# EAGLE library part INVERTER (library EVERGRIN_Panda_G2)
Inverter

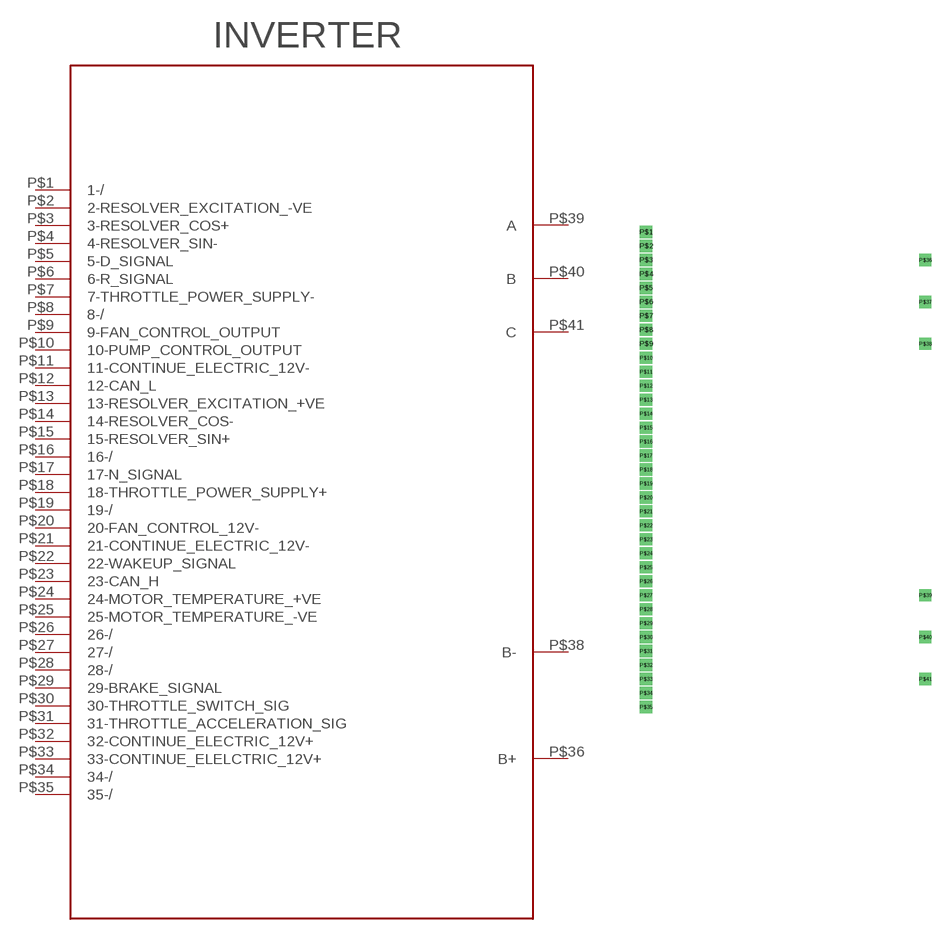
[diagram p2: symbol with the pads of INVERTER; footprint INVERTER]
Designator prefix -

## INVERTER  [INVERTER]
P$1  1-/
P$2  2-RESOLVER_EXCITATION_-VE
P$3  3-RESOLVER_COS+
P$4  4-RESOLVER_SIN-
P$5  5-D_SIGNAL
P$6  6-R_SIGNAL
P$7  7-THROTTLE_POWER_SUPPLY-
P$8  8-/
P$9  9-FAN_CONTROL_OUTPUT
P$10  10-PUMP_CONTROL_OUTPUT
P$11  11-CONTINUE_ELECTRIC_12V-
P$12  12-CAN_L
P$13  13-RESOLVER_EXCITATION_+VE
P$14  14-RESOLVER_COS-
P$15  15-RESOLVER_SIN+
P$16  16-/
P$17  17-N_SIGNAL
P$18  18-THROTTLE_POWER_SUPPLY+
P$19  19-/
P$20  20-FAN_CONTROL_12V-
P$21  21-CONTINUE_ELECTRIC_12V-
P$22  22-WAKEUP_SIGNAL
P$23  23-CAN_H
P$24  24-MOTOR_TEMPERATURE_+VE
P$25  25-MOTOR_TEMPERATURE_-VE
P$26  26-/
P$27  27-/
P$28  28-/
P$29  29-BRAKE_SIGNAL
P$30  30-THROTTLE_SWITCH_SIG
P$31  31-THROTTLE_ACCELERATION_SIG
P$32  32-CONTINUE_ELECTRIC_12V+
P$33  33-CONTINUE_ELELCTRIC_12V+
P$34  34-/
P$35  35-/
P$36  B+
P$38  B-
P$39  A
P$40  B
P$41  C

## Footprint INVERTER (pad centres in mm)
drill 0.6 square: P$1 -6.35,54.61; P$2 -6.35,53.34; P$3 -6.35,52.07; P$4 -6.35,50.8; P$5 -6.35,49.53; P$6 -6.35,48.26; P$7 -6.35,46.99; P$8 -6.35,45.72; P$9 -6.35,44.45; P$10 -6.35,43.18; P$11 -6.35,41.91; P$12 -6.35,40.64; P$13 -6.35,39.37; P$14 -6.35,38.1; P$15 -6.35,36.83; P$16 -6.35,35.56; P$17 -6.35,34.29; P$18 -6.35,33.02; P$19 -6.35,31.75; P$20 -6.35,30.48; P$21 -6.35,29.21; P$22 -6.35,27.94; P$23 -6.35,26.67; P$24 -6.35,25.4; P$25 -6.35,24.13; P$26 -6.35,22.86; P$27 -6.35,21.59; P$28 -6.35,20.32; P$29 -6.35,19.05; P$30 -6.35,17.78; P$31 -6.35,16.51; P$32 -6.35,15.24; P$33 -6.35,13.97; P$34 -6.35,12.7; P$35 -6.35,11.43; P$36 19.05,52.07; P$37 19.05,48.26; P$38 19.05,44.45; P$39 19.05,21.59; P$40 19.05,17.78; P$41 19.05,13.97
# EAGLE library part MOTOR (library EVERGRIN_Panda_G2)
Motor

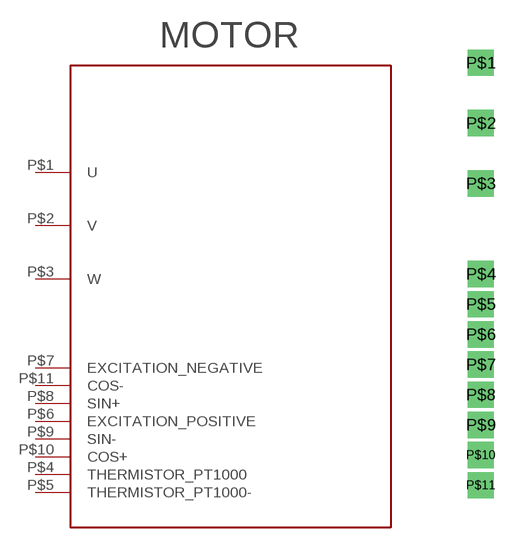
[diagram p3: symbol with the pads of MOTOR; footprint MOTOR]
Designator prefix -

## MOTOR  [MOTOR]
P$1  U
P$2  V
P$3  W
P$4  THERMISTOR_PT1000
P$5  THERMISTOR_PT1000-
P$6  EXCITATION_POSITIVE
P$7  EXCITATION_NEGATIVE
P$8  SIN+
P$9  SIN-
P$10  COS+
P$11  COS-

## Footprint MOTOR (pad centres in mm)
drill 0.6 square: P$1 -1.27,24.13; P$2 -1.27,21.59; P$3 -1.27,19.05; P$4 -1.27,15.24; P$5 -1.27,13.97; P$6 -1.27,12.7; P$7 -1.27,11.43; P$8 -1.27,10.16; P$9 -1.27,8.89; P$10 -1.27,7.62; P$11 -1.27,6.35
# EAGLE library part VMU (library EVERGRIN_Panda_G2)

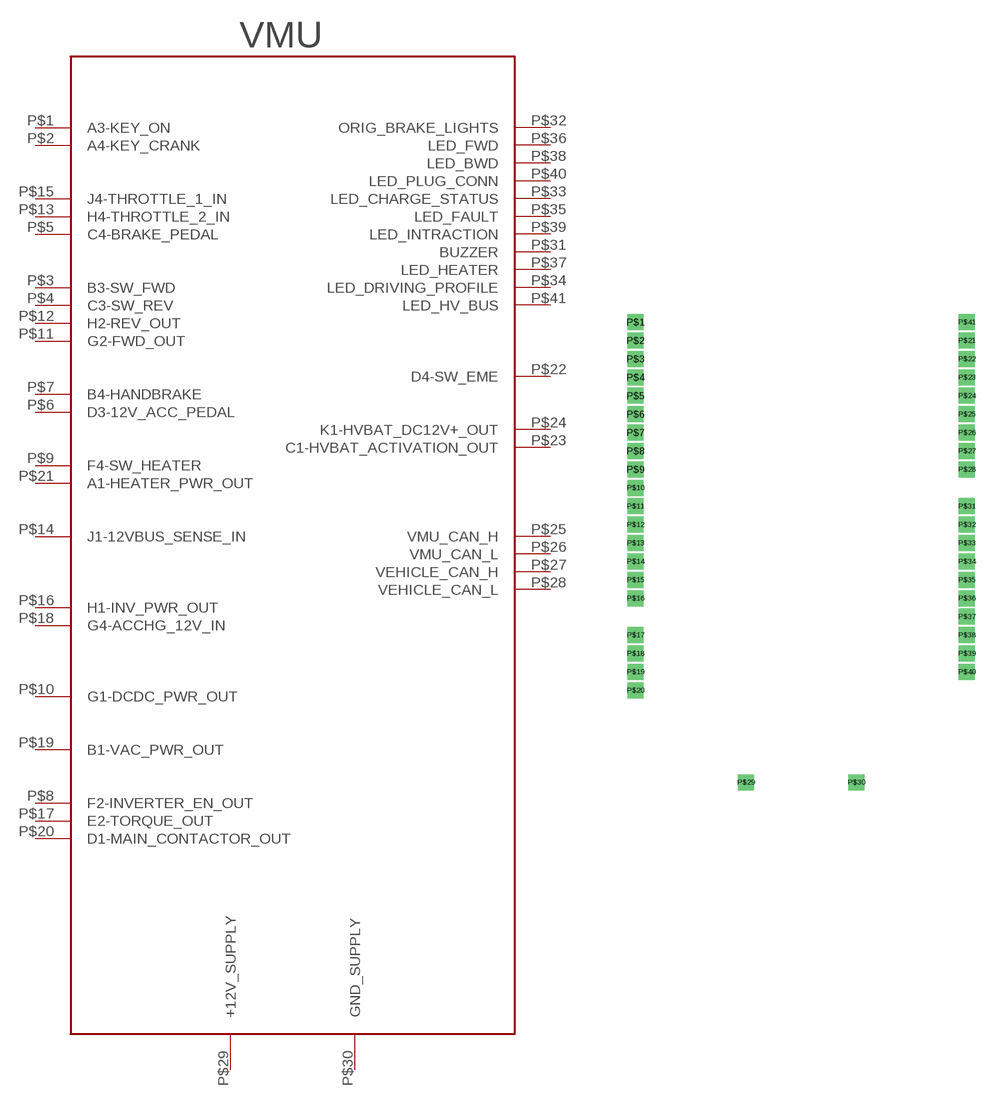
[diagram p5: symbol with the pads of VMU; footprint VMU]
Designator prefix -

## VMU  [VMU]
P$1  A3-KEY_ON  in
P$2  A4-KEY_CRANK  in
P$3  B3-SW_FWD  in
P$4  C3-SW_REV  in
P$5  C4-BRAKE_PEDAL  in
P$6  D3-12V_ACC_PEDAL
P$7  B4-HANDBRAKE  in
P$8  F2-INVERTER_EN_OUT  out
P$9  F4-SW_HEATER  in
P$10  G1-DCDC_PWR_OUT  out
P$11  G2-FWD_OUT  in
P$12  H2-REV_OUT  out
P$13  H4-THROTTLE_2_IN  in
P$14  J1-12VBUS_SENSE_IN  in
P$15  J4-THROTTLE_1_IN  in
P$16  H1-INV_PWR_OUT
P$17  E2-TORQUE_OUT  out
P$18  G4-ACCHG_12V_IN
P$19  B1-VAC_PWR_OUT  out
P$20  D1-MAIN_CONTACTOR_OUT  out
P$21  A1-HEATER_PWR_OUT  out
P$22  D4-SW_EME  in
P$23  C1-HVBAT_ACTIVATION_OUT  out
P$24  K1-HVBAT_DC12V+_OUT  out
P$25  VMU_CAN_H
P$26  VMU_CAN_L
P$27  VEHICLE_CAN_H
P$28  VEHICLE_CAN_L
P$29  +12V_SUPPLY
P$30  GND_SUPPLY
P$31  BUZZER  out
P$32  ORIG_BRAKE_LIGHTS  out
P$33  LED_CHARGE_STATUS  out
P$34  LED_DRIVING_PROFILE  out
P$35  LED_FAULT  out
P$36  LED_FWD  out
P$37  LED_HEATER  out
P$38  LED_BWD  out
P$39  LED_INTRACTION  out
P$40  LED_PLUG_CONN  out
P$41  LED_HV_BUS  out

## Footprint VMU (pad centres in mm)
drill 0.6 square: P$1 0,31.75; P$2 0,30.48; P$3 0,29.21; P$4 0,27.94; P$5 0,26.67; P$6 0,25.4; P$7 0,24.13; P$8 0,22.86; P$9 0,21.59; P$10 0,20.32; P$11 0,19.05; P$12 0,17.78; P$13 0,16.51; P$14 0,15.24; P$15 0,13.97; P$16 0,12.7; P$17 0,10.16; P$18 0,8.89; P$19 0,7.62; P$20 0,6.35; P$21 22.86,30.48; P$22 22.86,29.21; P$23 22.86,27.94; P$24 22.86,26.67; P$25 22.86,25.4; P$26 22.86,24.13; P$27 22.86,22.86; P$28 22.86,21.59; P$29 7.62,0; P$30 15.24,0; P$31 22.86,19.05; P$32 22.86,17.78; P$33 22.86,16.51; P$34 22.86,15.24; P$35 22.86,13.97; P$36 22.86,12.7; P$37 22.86,11.43; P$38 22.86,10.16; P$39 22.86,8.89; P$40 22.86,7.62; P$41 22.86,31.75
